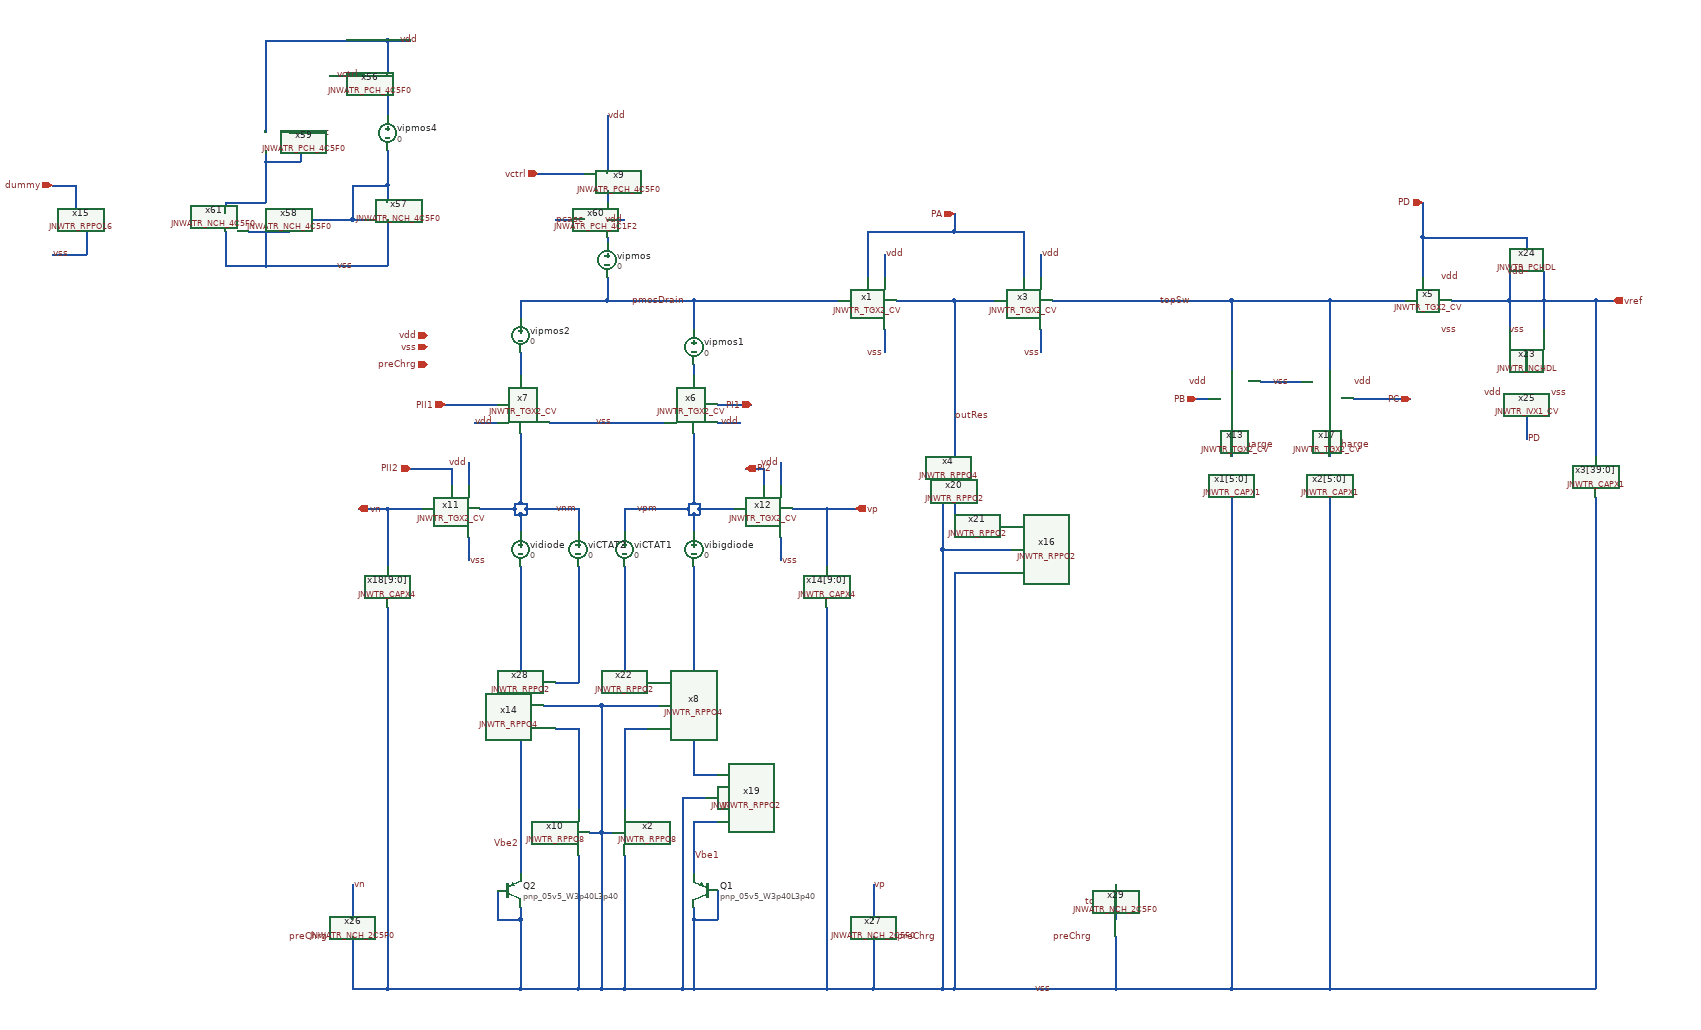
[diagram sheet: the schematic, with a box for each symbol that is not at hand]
v {xschem version=3.4.6 file_version=1.2}
G {}
K {}
V {}
S {}
E {}
N 1390 -1540 1390 -1270 {
lab=outRes}
N 1270 -1490 1270 -1450 {
lab=vss}
N 1270 -1620 1270 -1580 {
lab=vdd}
N 1240 -1660 1240 -1580 {
lab=PA}
N 1540 -1490 1540 -1450 {
lab=vss}
N 1540 -1620 1540 -1580 {
lab=vdd}
N 1510 -1660 1510 -1580 {
lab=PA}
N 1810 -1370 1830 -1370 {
lab=PB}
N 2080 -1370 2180 -1370 {
lab=PC}
N 2200 -1650 2200 -1580 {
lab=PD}
N 2500 -1540 2500 -1270 {
lab=vref}
N 560 -1330 600 -1330 {
lab=vdd}
N 980 -1360 1040 -1360 {
lab=PI1}
N 980 -1330 1020 -1330 {
lab=vdd}
N 690 -1330 890 -1330 {
lab=vss}
N 930 -1180 930 -1170 {
lab=vpm}
N 940 -1190 950 -1190 {
lab=vpm}
N 650 -1180 650 -1170 {
lab=vnm}
N 640 -1190 650 -1190 {
lab=vnm}
N 950 -1180 950 -1170 {
lab=vpm}
N 1170 -1180 1220 -1180 {
lab=vp}
N 1170 -1180 1170 -1080 {
lab=vp}
N 650 -1190 650 -1180 {
lab=vnm}
N 930 -1190 930 -1180 {
lab=vpm}
N 640 -1170 650 -1170 {
lab=vnm}
N 650 -1180 740 -1180 {
lab=vnm}
N 360 -1180 410 -1180 {
lab=vn}
N 410 -1180 410 -1080 {
lab=vn}
N 630 -1180 630 -1170 {
lab=vnm}
N 410 -1010 410 -350 {
lab=vss}
N 2040 -350 2500 -350 {
lab=vss}
N 2500 -1200 2500 -350 {
lab=vss}
N 2040 -1200 2040 -350 {
lab=vss}
N 1870 -350 2040 -350 {
lab=vss}
N 1870 -1200 1870 -350 {
lab=vss}
N 1170 -1010 1170 -350 {
lab=vss}
N 940 -350 1170 -350 {
lab=vss}
N 1670 -350 1870 -350 {
lab=vss}
N 940 -470 940 -350 {
lab=vss}
N 640 -470 640 -350 {
lab=vss}
N 410 -350 640 -350 {
lab=vss}
N 600 -520 600 -470 {
lab=vss}
N 600 -470 640 -470 {
lab=vss}
N 980 -520 980 -470 {
lab=vss}
N 940 -470 980 -470 {
lab=vss}
N 940 -490 940 -470 {
lab=vss}
N 1090 -1130 1090 -1090 {
lab=vss}
N 550 -1130 550 -1090 {
lab=vss}
N 1090 -1260 1090 -1220 {
lab=vdd}
N 550 -1260 550 -1220 {
lab=vdd}
N 670 -1760 750 -1760 {
lab=vctrl}
N 790 -1860 790 -1760 {
lab=vdd}
N 520 -1250 520 -1220 {
lab=PII2}
N 450 -1250 520 -1250 {
lab=PII2}
N 1030 -1250 1060 -1250 {
lab=PI2}
N 2500 -1540 2530 -1540 {
lab=vref}
N 1390 -1660 1510 -1660 {
lab=PA}
N 1390 -1690 1390 -1660 {
lab=PA}
N 1240 -1660 1390 -1660 {
lab=PA}
N 510 -1360 600 -1360 {
lab=PII1}
N -170 -1740 -130 -1740 {
lab=dummy}
N -130 -1740 -130 -1700 {
lab=dummy}
N -110 -1660 -110 -1620 {
lab=vss}
N -170 -1620 -110 -1620 {
lab=vss}
N 640 -490 640 -470 {
lab=vss}
N 820 -1180 930 -1180 {
lab=vpm}
N 940 -1170 950 -1170 {
lab=vpm}
N 920 -350 940 -350 {
lab=vss}
N 790 -1730 790 -1710 {
lab=#net1}
N 790 -1580 790 -1540 {
lab=pmosDrain}
N 640 -1540 790 -1540 {
lab=pmosDrain}
N 940 -1170 940 -1140 {
lab=vpm}
N 930 -1170 940 -1170 {
lab=vpm}
N 940 -640 940 -550 {
lab=Vbe1}
N 640 -350 740 -350 {
lab=vss}
N 740 -350 780 -350 {
lab=vss}
N 780 -350 820 -350 {
lab=vss}
N 940 -1080 940 -720 {
lab=#net2}
N 820 -350 920 -350 {
lab=vss}
N 1390 -1540 1460 -1540 {
lab=outRes}
N 940 -1540 1190 -1540 {
lab=pmosDrain}
N 940 -1310 940 -1190 {
lab=vpm}
N 930 -1190 940 -1190 {
lab=vpm}
N 950 -1180 1010 -1180 {
lab=vpm}
N 950 -1190 950 -1180 {
lab=vpm}
N 570 -1180 630 -1180 {
lab=vnm}
N 630 -1190 630 -1180 {
lab=vnm}
N 640 -1310 640 -1190 {
lab=vnm}
N 630 -1190 640 -1190 {
lab=vnm}
N 410 -1180 470 -1180 {
lab=vn}
N 1110 -1180 1170 -1180 {
lab=vp}
N 1060 -1250 1060 -1220 {
lab=PI2}
N 1870 -1540 1870 -1420 {
lab=topSw}
N 1870 -1320 1870 -1270 {
lab=Hcharge}
N 2040 -1540 2040 -1420 {
lab=topSw}
N 1870 -1540 2040 -1540 {
lab=topSw}
N 2040 -1320 2040 -1270 {
lab=Lcharge}
N 1920 -1400 1990 -1400 {
lab=vss}
N 2380 -1650 2380 -1630 {
lab=PD}
N 2200 -1650 2380 -1650 {
lab=PD}
N 2200 -1710 2200 -1650 {
lab=PD}
N 2350 -1590 2350 -1540 {
lab=vref}
N 2250 -1540 2350 -1540 {
lab=vref}
N 2410 -1590 2410 -1540 {
lab=vref}
N 2350 -1540 2410 -1540 {
lab=vref}
N 2380 -1340 2380 -1300 {
lab=PD}
N 2350 -1540 2350 -1490 {
lab=vref}
N 2410 -1540 2410 -1490 {
lab=vref}
N 2410 -1540 2500 -1540 {
lab=vref}
N 2380 -1450 2380 -1420 {
lab=#net3}
N 2040 -1540 2170 -1540 {
lab=topSw}
N 740 -1180 740 -1140 {
lab=vnm}
N 820 -1180 820 -1140 {
lab=vpm}
N 640 -1170 640 -1140 {
lab=vnm}
N 630 -1170 640 -1170 {
lab=vnm}
N 640 -1080 640 -550 {
lab=Vbe2}
N 920 -680 920 -350 {
lab=vss}
N 1560 -1540 1870 -1540 {
lab=topSw}
N 1290 -1540 1390 -1540 {
lab=outRes}
N 1250 -530 1250 -470 {
lab=vp}
N 1170 -350 1250 -350 {
lab=vss}
N 350 -530 350 -470 {
lab=vn}
N 350 -350 410 -350 {
lab=vss}
N 350 -440 350 -350 {
lab=vss}
N 1250 -440 1250 -350 {
lab=vss}
N 1670 -530 1670 -470 {
lab=topSw}
N 1670 -440 1670 -350 {
lab=vss}
N 940 -1430 940 -1410 {lab=#net4}
N 940 -1540 940 -1490 {lab=pmosDrain}
N 790 -1540 940 -1540 {
lab=pmosDrain}
N 640 -1540 640 -1510 {lab=pmosDrain}
N 640 -1450 640 -1410 {lab=#net5}
N 920 -680 960 -680 {lab=vss}
N 940 -720 980 -720 {lab=#net2}
N 940 -640 980 -640 {lab=Vbe1}
N 820 -580 820 -350 {lab=vss}
N 780 -620 800 -620 {lab=vss}
N 780 -620 780 -350 {lab=vss}
N 740 -580 740 -350 {lab=vss}
N 760 -620 780 -620 {lab=vss}
N 1370 -1110 1370 -350 {lab=vss}
N 1390 -350 1670 -350 {
lab=vss}
N 1250 -350 1370 -350 {
lab=vss}
N 1370 -1110 1490 -1110 {lab=vss}
N 1370 -1230 1370 -1110 {lab=vss}
N 1390 -1150 1470 -1150 {lab=#net6}
N 1390 -1190 1390 -1150 {lab=#net6}
N 1390 -1070 1470 -1070 {lab=vss}
N 1390 -1070 1390 -350 {lab=vss}
N 1370 -350 1390 -350 {
lab=vss}
N 410 -1990 410 -1930 {lab=vdd}
N 410 -1990 450 -1990 {lab=vdd}
N 410 -1740 410 -1710 {lab=#net7}
N 310 -1930 370 -1930 {lab=vctrl}
N 410 -1680 410 -1600 {lab=vss}
N 350 -1680 370 -1680 {lab=#net7}
N 200 -1680 200 -1600 {lab=vss}
N 200 -1780 200 -1710 {lab=pcasc}
N 200 -1990 200 -1830 {lab=vdd}
N 200 -1990 410 -1990 {lab=vdd}
N 260 -1830 290 -1830 {lab=pcasc}
N 350 -1740 410 -1740 {lab=#net7}
N 410 -1800 410 -1740 {lab=#net7}
N 350 -1740 350 -1680 {lab=#net7}
N 240 -1680 350 -1680 {lab=#net7}
N 260 -1830 260 -1780 {lab=pcasc}
N 200 -1780 260 -1780 {lab=pcasc}
N 240 -1830 260 -1830 {lab=pcasc}
N 200 -1800 200 -1780 {lab=pcasc}
N 790 -1680 820 -1680 {lab=vdd}
N 700 -1680 750 -1680 {lab=pcasc}
N 410 -1900 410 -1860 {lab=#net8}
N 200 -1600 410 -1600 {lab=vss}
N 170 -1660 240 -1660 {lab=#net7}
N 240 -1680 240 -1660 {lab=#net7}
N 130 -1600 200 -1600 {lab=vss}
N 130 -1660 130 -1600 {lab=vss}
N 130 -1710 130 -1690 {lab=pcasc}
N 130 -1710 200 -1710 {lab=pcasc}
N 790 -1650 790 -1640 {lab=#net9}
N 740 -800 740 -660 {lab=#net10}
N 740 -1080 740 -880 {lab=#net11}
N 820 -1080 820 -880 {lab=#net12}
N 820 -800 820 -660 {lab=#net13}
N 780 -840 880 -840 {lab=vss}
N 820 -880 860 -880 {lab=#net12}
N 820 -800 860 -800 {lab=#net13}
N 680 -840 780 -840 {lab=vss}
N 700 -800 740 -800 {lab=#net10}
N 780 -840 780 -620 {lab=vss}
N 700 -880 740 -880 {lab=#net11}
C {devices/ipin.sym} 480 -1480 0 0 {name=p1 lab=vdd}
C {devices/ipin.sym} 480 -1460 0 0 {name=p2 lab=vss
}
C {devices/lab_wire.sym} 1560 -350 0 0 {name=p4 sig_type=std_logic lab=vss
}
C {devices/lab_wire.sym} 1270 -1450 0 0 {name=p5 sig_type=std_logic lab=vss
}
C {devices/lab_wire.sym} 1270 -1620 0 1 {name=p6 sig_type=std_logic lab=vdd

}
C {devices/lab_wire.sym} 1540 -1450 0 0 {name=p9 sig_type=std_logic lab=vss
}
C {devices/lab_wire.sym} 1540 -1620 0 1 {name=p11 sig_type=std_logic lab=vdd

}
C {devices/lab_wire.sym} 1830 -1400 0 0 {name=p12 sig_type=std_logic lab=vdd

}
C {devices/lab_wire.sym} 2080 -1400 0 1 {name=p13 sig_type=std_logic lab=vdd

}
C {devices/lab_wire.sym} 2230 -1580 0 1 {name=p17 sig_type=std_logic lab=vdd

}
C {devices/lab_wire.sym} 800 -1330 0 0 {name=p18 sig_type=std_logic lab=vss
}
C {devices/lab_wire.sym} 560 -1330 0 1 {name=p19 sig_type=std_logic lab=vdd

}
C {devices/lab_wire.sym} 1020 -1330 0 0 {name=p20 sig_type=std_logic lab=vdd

}
C {JNW_TR_SKY130A/JNWTR_CAPX4.sym} 1170 -1020 0 0 {name=x14[9:0]}
C {JNW_TR_SKY130A/JNWTR_CAPX4.sym} 410 -1020 0 1 {name=x18[9:0]}
C {sky130_fd_pr/pnp_05v5.sym} 960 -520 0 1 {name=Q1
model=pnp_05v5_W3p40L3p40
m=8
spiceprefix=X
}
C {sky130_fd_pr/pnp_05v5.sym} 620 -520 0 0 {name=Q2
model=pnp_05v5_W3p40L3p40
m=1
spiceprefix=X
}
C {devices/lab_wire.sym} 1090 -1090 0 1 {name=p23 sig_type=std_logic lab=vss
}
C {devices/lab_wire.sym} 550 -1090 0 1 {name=p24 sig_type=std_logic lab=vss
}
C {devices/lab_wire.sym} 1090 -1260 0 0 {name=p25 sig_type=std_logic lab=vdd

}
C {devices/lab_wire.sym} 550 -1260 0 0 {name=p26 sig_type=std_logic lab=vdd

}
C {devices/ipin.sym} 670 -1760 0 0 {name=p27 lab=vctrl}
C {devices/lab_wire.sym} 790 -1860 0 1 {name=p28 sig_type=std_logic lab=vdd

}
C {devices/ipin.sym} 2200 -1710 1 0 {name=p8 lab=PD}
C {devices/ipin.sym} 1810 -1370 0 0 {name=p10 lab=PB}
C {devices/ipin.sym} 2180 -1370 2 0 {name=p15 lab=PC}
C {devices/ipin.sym} 1390 -1690 1 0 {name=p16 lab=PA}
C {devices/ipin.sym} 1030 -1250 2 1 {name=p31 lab=PI2}
C {devices/ipin.sym} -170 -1740 0 0 {name=p32 lab=dummy}
C {devices/ipin.sym} 510 -1360 0 0 {name=p33 lab=PII1}
C {devices/ipin.sym} 1040 -1360 2 0 {name=p34 lab=PI1}
C {devices/opin.sym} 2530 -1540 0 0 {name=p3 lab=vref}
C {devices/opin.sym} 1220 -1180 0 0 {name=p21 lab=vp}
C {devices/opin.sym} 360 -1180 2 0 {name=p22 lab=vn}
C {devices/ipin.sym} 450 -1250 0 0 {name=p29 lab=PII2}
C {devices/lab_wire.sym} -170 -1620 0 1 {name=p30 sig_type=std_logic lab=vss
}
C {JNW_TR_SKY130A/JNWTR_CAPX1.sym} 1870 -1210 0 0 {name=x1[5:0]}
C {JNW_TR_SKY130A/JNWTR_CAPX1.sym} 2040 -1210 0 0 {name=x2[5:0]}
C {JNW_TR_SKY130A/JNWTR_CAPX1.sym} 2500 -1210 0 0 {name=x3[39:0]}
C {JNW_ATR_SKY130A/JNWATR_PCH_4C5F0.sym} 750 -1760 0 0 {name=x9 }
C {devices/vsource.sym} 790 -1610 0 0 {name=vipmos value=0 savecurrent=true}
C {devices/vsource.sym} 940 -1110 0 0 {name=vibigdiode value=0 savecurrent=true}
C {JNW_TR_SKY130A/JNWTR_RPPO2.sym} 940 -720 1 0 {name=x18 }
C {devices/lab_wire.sym} 1870 -1290 0 1 {name=p35 sig_type=std_logic lab=Hcharge

}
C {devices/lab_wire.sym} 2040 -1290 0 1 {name=p36 sig_type=std_logic lab=Lcharge

}
C {devices/lab_wire.sym} 1390 -1340 0 1 {name=p37 sig_type=std_logic lab=outRes

}
C {JNW_TR_SKY130A/JNWTR_TGX2_CV.sym} 1180 -1540 0 0 {name=x1 }
C {JNW_TR_SKY130A/JNWTR_TGX2_CV.sym} 1450 -1540 0 0 {name=x3 }
C {JNW_TR_SKY130A/JNWTR_TGX2_CV.sym} 940 -1420 1 0 {name=x6 }
C {JNW_TR_SKY130A/JNWTR_TGX2_CV.sym} 640 -1420 3 1 {name=x7 }
C {JNW_TR_SKY130A/JNWTR_TGX2_CV.sym} 460 -1180 0 0 {name=x11 }
C {JNW_TR_SKY130A/JNWTR_TGX2_CV.sym} 1000 -1180 0 0 {name=x12 }
C {devices/lab_wire.sym} 2230 -1490 0 1 {name=p42 sig_type=std_logic lab=vss
}
C {devices/lab_wire.sym} 1940 -1400 0 1 {name=p38 sig_type=std_logic lab=vss
}
C {JNW_TR_SKY130A/JNWTR_TGX2_CV.sym} 2140 -1540 0 0 {name=x5 }
C {JNW_TR_SKY130A/JNWTR_TGX2_CV.sym} 1870 -1310 3 0 {name=x13 }
C {JNW_TR_SKY130A/JNWTR_TGX2_CV.sym} 2040 -1310 1 1 {name=x17 }
C {JNW_TR_SKY130A/JNWTR_NCHDL.sym} 2380 -1450 3 0 {name=x23 }
C {JNW_TR_SKY130A/JNWTR_PCHDL.sym} 2380 -1630 1 0 {name=x24 }
C {JNW_TR_SKY130A/JNWTR_IVX1_CV.sym} 2380 -1340 3 0 {name=x25 }
C {devices/lab_wire.sym} 2380 -1300 0 1 {name=p7 sig_type=std_logic lab=PD

}
C {devices/lab_wire.sym} 2340 -1380 0 0 {name=p14 sig_type=std_logic lab=vdd

}
C {devices/lab_wire.sym} 2380 -1590 1 1 {name=p39 sig_type=std_logic lab=vdd

}
C {devices/lab_wire.sym} 2380 -1490 1 0 {name=p40 sig_type=std_logic lab=vss
}
C {devices/lab_wire.sym} 2420 -1380 0 1 {name=p41 sig_type=std_logic lab=vss
}
C {JNW_TR_SKY130A/JNWTR_RPPO16.sym} -130 -1700 3 1 {name=x15 }
C {devices/lab_wire.sym} 830 -1540 0 1 {name=p43 sig_type=std_logic lab=pmosDrain

}
C {devices/vsource.sym} 820 -1110 0 0 {name=viCTAT1 value=0 savecurrent=true}
C {devices/lab_wire.sym} 640 -600 0 0 {name=p44 sig_type=std_logic lab=Vbe2

}
C {devices/vsource.sym} 740 -1110 0 0 {name=viCTAT2 value=0 savecurrent=true}
C {devices/vsource.sym} 640 -1110 0 0 {name=vidiode value=0 savecurrent=true}
C {devices/lab_wire.sym} 940 -580 0 1 {name=p45 sig_type=std_logic lab=Vbe1

}
C {devices/lab_wire.sym} 350 -530 0 1 {name=p55 sig_type=std_logic lab=vn

}
C {devices/lab_wire.sym} 1250 -530 0 1 {name=p56 sig_type=std_logic lab=vp

}
C {devices/ipin.sym} 480 -1430 0 0 {name=p57 lab=preChrg}
C {devices/lab_wire.sym} 310 -440 0 0 {name=p51 sig_type=std_logic lab=preChrg

}
C {devices/lab_wire.sym} 1290 -440 0 1 {name=p54 sig_type=std_logic lab=preChrg

}
C {devices/lab_wire.sym} 1630 -440 0 0 {name=p47 sig_type=std_logic lab=preChrg

}
C {devices/lab_wire.sym} 1800 -1540 0 0 {name=p46 sig_type=std_logic lab=topSw

}
C {devices/lab_wire.sym} 1670 -500 3 1 {name=p48 sig_type=std_logic lab=topSw

}
C {JNW_ATR_SKY130A/JNWATR_NCH_2C5F0.sym} 1630 -440 0 0 {name=x29 }
C {JNW_ATR_SKY130A/JNWATR_NCH_2C5F0.sym} 310 -440 0 0 {name=x26 }
C {JNW_ATR_SKY130A/JNWATR_NCH_2C5F0.sym} 1290 -440 0 1 {name=x27 }
C {devices/lab_wire.sym} 700 -1180 0 1 {name=p49 sig_type=std_logic lab=vnm
}
C {devices/lab_wire.sym} 880 -1180 0 0 {name=p50 sig_type=std_logic lab=vpm
}
C {devices/vsource.sym} 940 -1460 0 0 {name=vipmos1 value=0 savecurrent=true}
C {devices/vsource.sym} 640 -1480 0 0 {name=vipmos2 value=0 savecurrent=true}
C {JNW_TR_SKY130A/JNWTR_RPPO8.sym} 820 -660 1 0 {name=x2 }
C {JNW_TR_SKY130A/JNWTR_RPPO8.sym} 740 -660 3 1 {name=x10 }
C {JNW_TR_SKY130A/JNWTR_RPPO4.sym} 1390 -1270 1 0 {name=x4 }
C {JNW_TR_SKY130A/JNWTR_RPPO2.sym} 1390 -1150 1 0 {name=x20 }
C {JNW_TR_SKY130A/JNWTR_RPPO2.sym} 1430 -1150 1 0 {name=x21 }
C {JNW_ATR_SKY130A/JNWATR_PCH_4C5F0.sym} 370 -1930 0 0 {name=x56 }
C {devices/lab_wire.sym} 430 -1990 0 1 {name=p123 sig_type=std_logic lab=vdd

}
C {devices/lab_wire.sym} 320 -1930 0 1 {name=p124 sig_type=std_logic lab=vctrl

}
C {JNW_ATR_SKY130A/JNWATR_NCH_4C5F0.sym} 370 -1680 0 0 {name=x57 }
C {JNW_ATR_SKY130A/JNWATR_NCH_4C5F0.sym} 240 -1680 0 1 {name=x58 }
C {devices/lab_wire.sym} 260 -1830 0 1 {name=p125 sig_type=std_logic lab=pcasc

}
C {JNW_ATR_SKY130A/JNWATR_PCH_4C5F0.sym} 240 -1830 0 1 {name=x59 }
C {JNW_ATR_SKY130A/JNWATR_PCH_4C1F2.sym} 750 -1680 0 0 {name=x60 }
C {devices/lab_wire.sym} 820 -1680 0 0 {name=p126 sig_type=std_logic lab=vdd

}
C {devices/lab_wire.sym} 700 -1680 0 1 {name=p127 sig_type=std_logic lab=pcasc

}
C {devices/vsource.sym} 410 -1830 0 0 {name=vipmos4 value=0 savecurrent=true}
C {devices/lab_wire.sym} 320 -1600 0 1 {name=p128 sig_type=std_logic lab=vss
}
C {JNW_ATR_SKY130A/JNWATR_NCH_4C5F0.sym} 170 -1660 0 1 {name=x61 }
C {JNW_TR_SKY130A/JNWTR_RPPO2.sym} 980 -720 1 0 {name=x19 }
C {JNW_TR_SKY130A/JNWTR_RPPO2.sym} 820 -880 1 0 {name=x22 }
C {JNW_TR_SKY130A/JNWTR_RPPO2.sym} 740 -880 3 1 {name=x28 }
C {JNW_TR_SKY130A/JNWTR_RPPO4.sym} 860 -880 1 0 {name=x8 }
C {JNW_TR_SKY130A/JNWTR_RPPO4.sym} 700 -800 3 0 {name=x14 }
C {JNW_TR_SKY130A/JNWTR_RPPO2.sym} 1470 -1150 1 0 {name=x16 }
